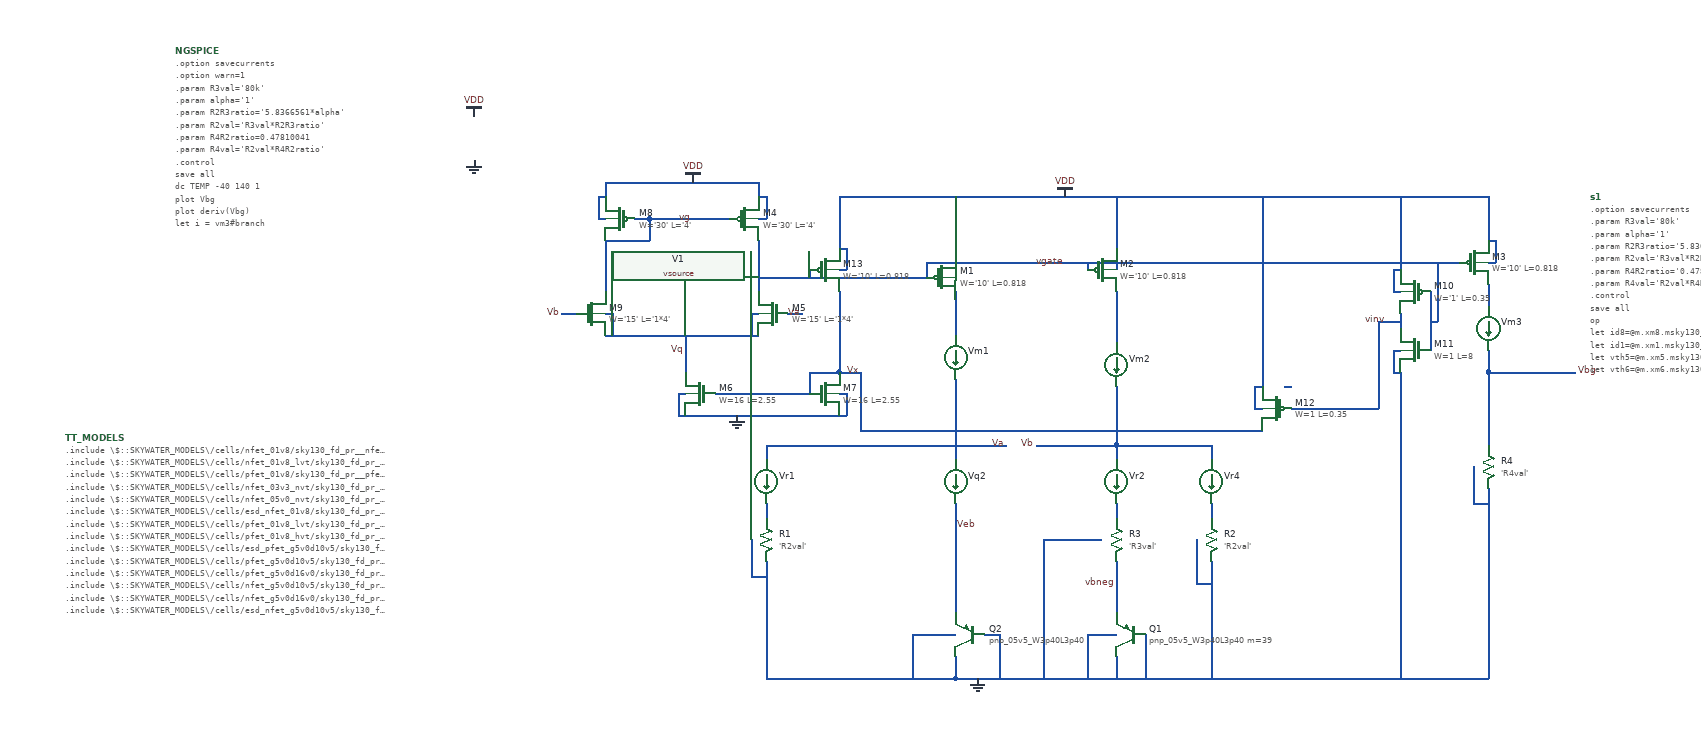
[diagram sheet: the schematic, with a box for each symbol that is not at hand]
v {xschem version=2.9.9 file_version=1.2 }
G {}
K {}
V {}
S {}
E {}
N 210 -180 460 -180 { lab=Va}
N 590 -180 690 -180 { lab=Vb}
N 690 -180 820 -180 { lab=Vb}
N 470 110 470 140 { lab=GND}
N 470 140 570 140 { lab=GND}
N 280 140 470 140 { lab=GND}
N 410 80 470 80 { lab=GND}
N 410 80 410 140 { lab=GND}
N 530 -180 540 -180 { lab=Va}
N 400 -520 620 -520 { lab=VDD}
N 620 -520 880 -520 { lab=VDD}
N 1200 -280 1320 -280 { lab=Vbg}
N 690 -180 690 -160 { lab=Vb}
N 690 -260 690 -180 { lab=Vb}
N 1200 -310 1200 -280 { lab=Vbg}
N 1200 -280 1200 -180 { lab=Vbg}
N 690 -100 690 -80 { lab=#net1}
N 820 -180 820 -160 { lab=Vb}
N 820 -100 820 -80 { lab=#net2}
N 210 -180 210 -160 { lab=Va}
N 210 -100 210 -80 { lab=#net3}
N 690 -390 690 -320 { lab=#net4}
N 690 -20 690 0 { lab=vbneg}
N 690 0 690 40 { lab=vbneg}
N 690 40 690 50 { lab=vbneg}
N 570 140 690 140 { lab=GND}
N 210 -20 210 140 { lab=GND}
N 820 -20 820 140 { lab=GND}
N 1200 -120 1200 140 { lab=GND}
N 620 140 880 140 { lab=GND}
N 730 80 730 140 { lab=GND}
N 470 -180 470 -160 { lab=Va}
N 690 110 690 140 { lab=GND}
N 650 80 690 80 { lab=GND}
N 650 80 650 140 { lab=GND}
N 510 80 530 80 { lab=GND}
N 530 80 530 140 { lab=GND}
N 190 -50 190 0 { lab=GND}
N 190 0 210 0 { lab=GND}
N 800 -50 800 10 { lab=GND}
N 800 10 820 10 { lab=GND}
N 590 -50 670 -50 { lab=GND}
N 590 -50 590 140 { lab=GND}
N 1180 -150 1180 -100 { lab=GND}
N 1180 -100 1200 -100 { lab=GND}
N 470 -100 470 50 { lab=Veb}
N 690 -460 690 -450 { lab=VDD}
N 1200 -380 1200 -370 { lab=#net5}
N 470 -270 470 -170 { lab=Va}
N 580 -180 590 -180 { lab=Vb}
N 470 -390 470 -330 { lab=#net6}
N 690 -450 690 -420 { lab=VDD}
N 430 -430 430 -420 { lab=vgate}
N 470 -450 470 -420 { lab=VDD}
N -10 -460 50 -460 { lab=vg}
N 50 -490 50 -460 { lab=vg}
N 30 -490 50 -490 { lab=vg}
N 50 -490 160 -490 { lab=vg}
N -10 -540 -10 -520 { lab=VDD}
N -10 -540 200 -540 { lab=VDD}
N 200 -540 200 -520 { lab=VDD}
N -10 -460 -10 -390 { lab=vg}
N 200 -460 200 -390 { lab=vgate}
N 240 -360 260 -360 { lab=Va}
N -70 -360 -50 -360 { lab=Vb}
N -10 -330 200 -330 { lab=Vq}
N 200 -490 210 -490 { lab=VDD}
N 210 -520 210 -490 { lab=VDD}
N 200 -520 210 -520 { lab=VDD}
N -20 -490 -10 -490 { lab=VDD}
N -20 -520 -20 -490 { lab=VDD}
N -20 -520 -10 -520 { lab=VDD}
N -10 -360 0 -360 { lab=Vq}
N 0 -360 0 -330 { lab=Vq}
N 190 -360 200 -360 { lab=Vq}
N 190 -360 190 -330 { lab=Vq}
N 90 -250 100 -250 { lab=GND}
N 90 -250 90 -220 { lab=GND}
N 90 -220 100 -220 { lab=GND}
N 100 -330 100 -280 { lab=Vq}
N 140 -250 270 -250 { lab=Vx}
N 310 -250 320 -250 { lab=GND}
N 310 -390 310 -280 { lab=Vx}
N 310 -520 360 -520 { lab=VDD}
N 170 -220 310 -220 { lab=GND}
N 100 -220 170 -220 { lab=GND}
N 270 -280 270 -250 { lab=Vx}
N 270 -280 310 -280 { lab=Vx}
N 310 -520 310 -450 { lab=VDD}
N 360 -520 400 -520 { lab=VDD}
N 430 -420 430 -410 { lab=vgate}
N 200 -410 360 -410 { lab=vgate}
N 320 -250 320 -220 { lab=GND}
N 310 -220 320 -220 { lab=GND}
N 270 -420 270 -410 { lab=vgate}
N 310 -420 320 -420 { lab=VDD}
N 320 -450 320 -420 { lab=VDD}
N 310 -450 320 -450 { lab=VDD}
N 1080 -520 1080 -420 { lab=VDD}
N 1120 -390 1120 -310 { lab=vgate}
N 1070 -390 1080 -390 { lab=VDD}
N 1070 -420 1070 -390 { lab=VDD}
N 1070 -420 1080 -420 { lab=VDD}
N 1080 -360 1080 -340 { lab=vinv}
N 1070 -310 1080 -310 { lab=GND}
N 1070 -310 1070 -280 { lab=GND}
N 1070 -280 1080 -280 { lab=GND}
N 1080 -280 1080 140 { lab=GND}
N 1120 -350 1130 -350 { lab=vgate}
N 1130 -430 1130 -350 { lab=vgate}
N 890 -520 890 -260 { lab=VDD}
N 880 -230 890 -230 { lab=VDD}
N 880 -260 880 -230 { lab=VDD}
N 920 -260 930 -260 { lab=#net7}
N 1050 -350 1050 -230 { lab=vinv}
N 1050 -350 1080 -350 { lab=vinv}
N 880 -520 1170 -520 { lab=VDD}
N 880 140 1170 140 { lab=GND}
N 340 -200 890 -200 { lab=Vx}
N 340 -280 340 -200 { lab=Vx}
N 310 -280 340 -280 { lab=Vx}
N 870 -430 1160 -430 { lab=vgate}
N 460 -180 530 -180 { lab=Va}
N 210 140 280 140 { lab=GND}
N 470 -520 470 -450 { lab=VDD}
N 690 -520 690 -460 { lab=VDD}
N 360 -410 430 -410 { lab=vgate}
N 430 -430 620 -430 { lab=vgate}
N 620 -430 870 -430 { lab=vgate}
N 650 -430 650 -420 { lab=vgate}
N 880 -260 890 -260 { lab=VDD}
N 1170 -520 1200 -520 { lab=VDD}
N 930 -230 1050 -230 { lab=vinv}
N 1170 140 1200 140 { lab=GND}
N 1200 -400 1200 -380 { lab=#net5}
N 1200 -430 1210 -430 { lab=VDD}
N 1210 -460 1210 -430 { lab=VDD}
N 1200 -460 1210 -460 { lab=VDD}
N 1200 -520 1200 -460 { lab=VDD}
N 470 -420 470 -410 { lab=VDD}
C {sky130_fd_pr/pnp_05v5.sym} 490 80 0 1 {name=Q2
model=pnp_05v5_W3p40L3p40
spiceprefix=X
}
C {devices/gnd.sym} 500 140 0 0 {name=l1 lab=GND}
C {devices/lab_pin.sym} 1320 -280 0 1 {name=l3 lab=Vbg}
C {devices/lab_pin.sym} 540 -180 3 0 {name=l5 lab=Va}
C {devices/lab_pin.sym} 580 -180 3 0 {name=l6 lab=Vb}
C {devices/code.sym} -750 -190 0 0 {name=TT_MODELS
only_toplevel=true
format="tcleval( @value )"
value="
.include \\\\$::SKYWATER_MODELS\\\\/cells/nfet_01v8/sky130_fd_pr__nfet_01v8__tt.corner.spice
.include \\\\$::SKYWATER_MODELS\\\\/cells/nfet_01v8_lvt/sky130_fd_pr__nfet_01v8_lvt__tt.corner.spice
.include \\\\$::SKYWATER_MODELS\\\\/cells/pfet_01v8/sky130_fd_pr__pfet_01v8__tt.corner.spice
.include \\\\$::SKYWATER_MODELS\\\\/cells/nfet_03v3_nvt/sky130_fd_pr__nfet_03v3_nvt__tt.corner.spice
.include \\\\$::SKYWATER_MODELS\\\\/cells/nfet_05v0_nvt/sky130_fd_pr__nfet_05v0_nvt__tt.corner.spice
.include \\\\$::SKYWATER_MODELS\\\\/cells/esd_nfet_01v8/sky130_fd_pr__esd_nfet_01v8__tt.corner.spice
.include \\\\$::SKYWATER_MODELS\\\\/cells/pfet_01v8_lvt/sky130_fd_pr__pfet_01v8_lvt__tt.corner.spice
.include \\\\$::SKYWATER_MODELS\\\\/cells/pfet_01v8_hvt/sky130_fd_pr__pfet_01v8_hvt__tt.corner.spice
.include \\\\$::SKYWATER_MODELS\\\\/cells/esd_pfet_g5v0d10v5/sky130_fd_pr__esd_pfet_g5v0d10v5__tt.corner.spice
.include \\\\$::SKYWATER_MODELS\\\\/cells/pfet_g5v0d10v5/sky130_fd_pr__pfet_g5v0d10v5__tt.corner.spice
.include \\\\$::SKYWATER_MODELS\\\\/cells/pfet_g5v0d16v0/sky130_fd_pr__pfet_g5v0d16v0__tt.corner.spice
.include \\\\$::SKYWATER_MODELS\\\\/cells/nfet_g5v0d10v5/sky130_fd_pr__nfet_g5v0d10v5__tt.corner.spice
.include \\\\$::SKYWATER_MODELS\\\\/cells/nfet_g5v0d16v0/sky130_fd_pr__nfet_g5v0d16v0__tt_discrete.corner.spice
.include \\\\$::SKYWATER_MODELS\\\\/cells/esd_nfet_g5v0d10v5/sky130_fd_pr__esd_nfet_g5v0d10v5__tt.corner.spice
.include \\\\$::SKYWATER_MODELS\\\\/models/corners/tt/nonfet.spice
* Mismatch parameters
.include \\\\$::SKYWATER_MODELS\\\\/cells/nfet_01v8/sky130_fd_pr__nfet_01v8__mismatch.corner.spice
.include \\\\$::SKYWATER_MODELS\\\\/cells/pfet_01v8/sky130_fd_pr__pfet_01v8__mismatch.corner.spice
.include \\\\$::SKYWATER_MODELS\\\\/cells/nfet_01v8_lvt/sky130_fd_pr__nfet_01v8_lvt__mismatch.corner.spice
.include \\\\$::SKYWATER_MODELS\\\\/cells/pfet_01v8_lvt/sky130_fd_pr__pfet_01v8_lvt__mismatch.corner.spice
.include \\\\$::SKYWATER_MODELS\\\\/cells/pfet_01v8_hvt/sky130_fd_pr__pfet_01v8_hvt__mismatch.corner.spice
.include \\\\$::SKYWATER_MODELS\\\\/cells/nfet_g5v0d10v5/sky130_fd_pr__nfet_g5v0d10v5__mismatch.corner.spice
.include \\\\$::SKYWATER_MODELS\\\\/cells/pfet_g5v0d10v5/sky130_fd_pr__pfet_g5v0d10v5__mismatch.corner.spice
.include \\\\$::SKYWATER_MODELS\\\\/cells/nfet_05v0_nvt/sky130_fd_pr__nfet_05v0_nvt__mismatch.corner.spice
.include \\\\$::SKYWATER_MODELS\\\\/cells/nfet_03v3_nvt/sky130_fd_pr__nfet_03v3_nvt__mismatch.corner.spice
* Resistor\\\\$::SKYWATER_MODELS\\\\/Capacitor
.include \\\\$::SKYWATER_MODELS\\\\/models/r+c/res_typical__cap_typical.spice
.include \\\\$::SKYWATER_MODELS\\\\/models/r+c/res_typical__cap_typical__lin.spice
* Special cells
.include \\\\$::SKYWATER_MODELS\\\\/models/corners/tt/specialized_cells.spice
* All models
.include \\\\$::SKYWATER_MODELS\\\\/models/all.spice
.include \\\\$::SKYWATER_MODELS\\\\/cells/pnp_05v5/sky130_fd_pr__pnp_05v5_W3p40L3p40.model.spice
* Corner
.include \\\\$::SKYWATER_MODELS\\\\/models/corners/tt/rf.spice
"}
C {devices/code_shown.sym} -600 -720 0 0 {name=NGSPICE
only_toplevel=true
spice_ignore=true
value="
.option savecurrents
.option warn=1
.param R3val='80k'
.param alpha='1'
.param R2R3ratio='5.8366561*alpha'
.param R2val='R3val*R2R3ratio' 
.param R4R2ratio=0.47810041
.param R4val='R2val*R4R2ratio'
.control
save all
dc TEMP -40 140 1
plot Vbg
plot deriv(Vbg)
let i = vm3#branch
let indx = 67
*indx is the index of temperature sweep for 27degC
echo 'Vbg @ 27degC'
let vbg27c = vbg[indx]
print vbg27c
echo 'dVbe/degC & ppm @ 27degC'
print deriv(vbg)[indx] deriv(vbg)[indx]/vbg27c
echo 'ppm real'
print (vbg[110]-vbg[40])/vbg[67]/(70-0)*1e6
plot deriv(vbg)/vbg27c
plot v(va, vb) vs i
plot vm1#branch vm2#branch vm3#branch
let vsg = vdd - vgate
let vsd1 = vdd - va
let vsd2 = vdd - vb
let vsd3 = vdd - vbg
let vthp = @m.xm1.msky130_fd_pr__pfet_01v8_lvt['vth']
let vov = vsg - vthp
plot vov vsd1 vsd2 vsd3
let deltav = vb - vbneg
let r4 =vbg/@r4[i]
let r1 =va/@r1[i]
let r2 =vb/@r2[i]
let r3 =deltav/@r3[i]
let vptat =(r2/r3*deltav)
let sum = veb+vptat
plot veb vptat sum
plot deriv(veb) deriv(vptat)
let TCratio=deriv(veb)/deriv(vptat)
plot TCratio
plot vb - va
echo 'alpha correction factor'
let alpha=TCratio[indx]
print alpha
let gm1=@m.xm1.msky130_fd_pr__pfet_01v8_lvt[gm]
let gm2=@m.xm2.msky130_fd_pr__pfet_01v8_lvt[gm]
let Av2=gm2 * ((r3 + r3/ln(39)) * r2 / (r3 + r3/ln(39) + r2) )
let Av1=gm1 * (r1 * r3/ln(39))/(r1 + r3/ln(39))
plot Av1 Av2 Av2/Av1
*write tsmc_bandgap_temp.raw
*op
*write tsmc_bandgap_op.raw
*print vbg 
*print (vb - vbneg)
.endc
" }
C {devices/vsource.sym} -190 -600 0 0 {name=V1 net_name=true value=1.8}
C {devices/vdd.sym} 620 -520 0 0 {name=l7 lab=VDD}
C {devices/vdd.sym} -190 -630 0 0 {name=l8 lab=VDD}
C {devices/gnd.sym} -190 -570 0 0 {name=l9 lab=GND}
C {devices/ammeter.sym} 820 -130 0 0 {name=Vr4}
C {devices/ammeter.sym} 690 -130 0 0 {name=Vr2}
C {devices/ammeter.sym} 470 -300 0 0 {name=Vm1}
C {devices/ammeter.sym} 690 -290 0 0 {name=Vm2}
C {devices/ammeter.sym} 1200 -340 0 0 {name=Vm3}
C {devices/ammeter.sym} 210 -130 0 0 {name=Vr1}
C {devices/ammeter.sym} 470 -130 0 0 {name=Vq2}
C {sky130_fd_pr/pnp_05v5.sym} 710 80 0 1 {name=Q1
model="pnp_05v5_W3p40L3p40 m=39"
spiceprefix=X
}
C {devices/lab_pin.sym} 690 10 0 0 {name=l4 lab=vbneg}
C {devices/lab_pin.sym} 470 -70 2 0 {name=l10 lab=Veb}
C {devices/lab_wire.sym} 620 -430 0 0 {name=l11 lab=vgate}
C {devices/res.sym} 690 -50 0 0 {name=R3
value='R3val'
footprint=1206
device=resistor
m=1
tc1=-1.47e-3
tc2=2.7e-6}
C {devices/res.sym} 1200 -150 0 0 {name=R4
value='R4val'
footprint=1206
device=resistor
m=1
tc1=-1.47e-3
tc2=2.7e-6}
C {devices/res.sym} 210 -50 0 0 {name=R1
value='R2val'
footprint=1206
device=resistor
m=1
tc1=-1.47e-3
tc2=2.7e-6}
C {devices/res.sym} 820 -50 0 0 {name=R2
value='R2val'
footprint=1206
device=resistor
m=1
tc1=-1.47e-3
tc2=2.7e-6}
C {devices/vdd.sym} 110 -540 0 0 {name=l14 lab=VDD}
C {devices/lab_pin.sym} -70 -360 3 0 {name=l15 lab=Vb}
C {devices/lab_pin.sym} 260 -360 3 0 {name=l16 lab=Va}
C {devices/gnd.sym} 170 -220 0 0 {name=l17 lab=GND}
C {sky130_fd_pr/pfet_01v8_lvt.sym} 180 -490 0 0 {name=M4
L='4'
W='30'
nf=1
mult=1
ad="'int((nf+1)/2) * W/nf * 0.29'" 
pd="'2*int((nf+1)/2) * (W/nf + 0.29)'"
as="'int((nf+2)/2) * W/nf * 0.29'" 
ps="'2*int((nf+2)/2) * (W/nf + 0.29)'"
nrd="'0.29 / W'" nrs="'0.29 / W'"
sa=0 sb=0 sd=0
model=pfet_01v8_lvt
spiceprefix=X
}
C {sky130_fd_pr/nfet_01v8_lvt.sym} 220 -360 0 1 {name=M5
L='1*4'
W='15'
nf=1
mult=16
ad="'int((nf+1)/2) * W/nf * 0.29'" 
pd="'2*int((nf+1)/2) * (W/nf + 0.29)'"
as="'int((nf+2)/2) * W/nf * 0.29'" 
ps="'2*int((nf+2)/2) * (W/nf + 0.29)'"
nrd="'0.29 / W'" nrs="'0.29 / W'"
sa=0 sb=0 sd=0
model=nfet_01v8_lvt
spiceprefix=X
}
C {sky130_fd_pr/nfet_01v8_lvt.sym} 120 -250 0 1 {name=M6
L=2.55
W=16
nf=1
mult=16
ad="'int((nf+1)/2) * W/nf * 0.29'" 
pd="'2*int((nf+1)/2) * (W/nf + 0.29)'"
as="'int((nf+2)/2) * W/nf * 0.29'" 
ps="'2*int((nf+2)/2) * (W/nf + 0.29)'"
nrd="'0.29 / W'" nrs="'0.29 / W'"
sa=0 sb=0 sd=0
model=nfet_01v8_lvt
spiceprefix=X
}
C {sky130_fd_pr/pfet_01v8_lvt.sym} 10 -490 0 1 {name=M8
L='4'
W='30'
nf=1
mult=1
ad="'int((nf+1)/2) * W/nf * 0.29'" 
pd="'2*int((nf+1)/2) * (W/nf + 0.29)'"
as="'int((nf+2)/2) * W/nf * 0.29'" 
ps="'2*int((nf+2)/2) * (W/nf + 0.29)'"
nrd="'0.29 / W'" nrs="'0.29 / W'"
sa=0 sb=0 sd=0
model=pfet_01v8_lvt
spiceprefix=X
}
C {sky130_fd_pr/nfet_01v8_lvt.sym} -30 -360 0 0 {name=M9
L='1*4'
W='15'
nf=1
mult=16
ad="'int((nf+1)/2) * W/nf * 0.29'" 
pd="'2*int((nf+1)/2) * (W/nf + 0.29)'"
as="'int((nf+2)/2) * W/nf * 0.29'" 
ps="'2*int((nf+2)/2) * (W/nf + 0.29)'"
nrd="'0.29 / W'" nrs="'0.29 / W'"
sa=0 sb=0 sd=0
model=nfet_01v8_lvt
spiceprefix=X
}
C {sky130_fd_pr/pfet_01v8_lvt.sym} 1100 -390 0 1 {name=M10
L=0.35
W='1'
nf=1
mult=50
ad="'int((nf+1)/2) * W/nf * 0.29'" 
pd="'2*int((nf+1)/2) * (W/nf + 0.29)'"
as="'int((nf+2)/2) * W/nf * 0.29'" 
ps="'2*int((nf+2)/2) * (W/nf + 0.29)'"
nrd="'0.29 / W'" nrs="'0.29 / W'"
sa=0 sb=0 sd=0
model=pfet_01v8_lvt
spiceprefix=X
}
C {sky130_fd_pr/nfet_01v8_lvt.sym} 1100 -310 0 1 {name=M11
L=8
W=1
nf=1
mult=1
ad="'int((nf+1)/2) * W/nf * 0.29'" 
pd="'2*int((nf+1)/2) * (W/nf + 0.29)'"
as="'int((nf+2)/2) * W/nf * 0.29'" 
ps="'2*int((nf+2)/2) * (W/nf + 0.29)'"
nrd="'0.29 / W'" nrs="'0.29 / W'"
sa=0 sb=0 sd=0
model=nfet_01v8_lvt
spiceprefix=X
}
C {sky130_fd_pr/pfet_01v8_lvt.sym} 910 -230 0 1 {name=M12
L=0.35
W=1
nf=1
mult=1
ad="'int((nf+1)/2) * W/nf * 0.29'" 
pd="'2*int((nf+1)/2) * (W/nf + 0.29)'"
as="'int((nf+2)/2) * W/nf * 0.29'" 
ps="'2*int((nf+2)/2) * (W/nf + 0.29)'"
nrd="'0.29 / W'" nrs="'0.29 / W'"
sa=0 sb=0 sd=0
model=pfet_01v8_lvt
spiceprefix=X
}
C {devices/lab_pin.sym} 110 -490 1 0 {name=l2 lab=vg}
C {devices/lab_pin.sym} 340 -280 1 0 {name=l12 lab=Vx}
C {devices/lab_pin.sym} 1060 -350 0 0 {name=l13 lab=vinv}
C {devices/lab_pin.sym} 100 -310 0 0 {name=l18 lab=Vq}
C {devices/code_shown.sym} 1340 -520 0 0 {name=s1 
only_toplevel=true 
spice_ignore=false
value="
.option savecurrents
.param R3val='80k'
.param alpha='1'
.param R2R3ratio='5.8366561*alpha'
.param R2val='R3val*R2R3ratio'
.param R4R2ratio='0.47810041'
.param R4val='R2val*R4R2ratio'
.control
save all
op
let id8=@m.xm8.msky130_fd_pr__pfet_01v8_lvt[id]
let id1=@m.xm1.msky130_fd_pr__pfet_01v8_lvt[id]
let vth5=@m.xm5.msky130_fd_pr__nfet_01v8_lvt[vth]
let vth6=@m.xm6.msky130_fd_pr__nfet_01v8_lvt[vth]
let wm8=@m.xm8.msky130_fd_pr__pfet_01v8_lvt[w]
let mm8=@m.xm8.msky130_fd_pr__pfet_01v8_lvt[m]
let weff8=wm8*mm8
let jd8=id8/weff8
let wm1=@m.xm1.msky130_fd_pr__pfet_01v8_lvt[w]
let mm1=@m.xm1.msky130_fd_pr__pfet_01v8_lvt[m]
let weff1=wm1*mm1
let jd1=id1/weff1
print vbg vgate vg va vb vx vinv vq
dc temp 27 0 -1
plot Vbg
dc temp 27 70 1
plot Vbg
.endc
"}
C {sky130_fd_pr/nfet_01v8_lvt.sym} 290 -250 0 0 {name=M7
L=2.55
W=16
nf=1
mult=16
ad="'int((nf+1)/2) * W/nf * 0.29'" 
pd="'2*int((nf+1)/2) * (W/nf + 0.29)'"
as="'int((nf+2)/2) * W/nf * 0.29'" 
ps="'2*int((nf+2)/2) * (W/nf + 0.29)'"
nrd="'0.29 / W'" nrs="'0.29 / W'"
sa=0 sb=0 sd=0
model=nfet_01v8_lvt
spiceprefix=X
}
C {sky130_fd_pr/pfet_01v8_lvt.sym} 290 -420 0 0 {name=M13
L=0.818
W='10'
nf=1
mult=1
ad="'int((nf+1)/2) * W/nf * 0.29'" 
pd="'2*int((nf+1)/2) * (W/nf + 0.29)'"
as="'int((nf+2)/2) * W/nf * 0.29'" 
ps="'2*int((nf+2)/2) * (W/nf + 0.29)'"
nrd="'0.29 / W'" nrs="'0.29 / W'"
sa=0 sb=0 sd=0
model=pfet_01v8_lvt
spiceprefix=X
}
C {sky130_fd_pr/pfet_01v8_lvt.sym} 450 -410 0 0 {name=M1
L=0.818
W='10'
nf=1
mult=1
ad="'int((nf+1)/2) * W/nf * 0.29'" 
pd="'2*int((nf+1)/2) * (W/nf + 0.29)'"
as="'int((nf+2)/2) * W/nf * 0.29'" 
ps="'2*int((nf+2)/2) * (W/nf + 0.29)'"
nrd="'0.29 / W'" nrs="'0.29 / W'"
sa=0 sb=0 sd=0
model=pfet_01v8_lvt
spiceprefix=X
}
C {sky130_fd_pr/pfet_01v8_lvt.sym} 670 -420 0 0 {name=M2
L=0.818
W='10'
nf=1
mult=1
ad="'int((nf+1)/2) * W/nf * 0.29'" 
pd="'2*int((nf+1)/2) * (W/nf + 0.29)'"
as="'int((nf+2)/2) * W/nf * 0.29'" 
ps="'2*int((nf+2)/2) * (W/nf + 0.29)'"
nrd="'0.29 / W'" nrs="'0.29 / W'"
sa=0 sb=0 sd=0
model=pfet_01v8_lvt
spiceprefix=X
}
C {sky130_fd_pr/pfet_01v8_lvt.sym} 1180 -430 0 0 {name=M3
L=0.818
W='10'
nf=1
mult=1
ad="'int((nf+1)/2) * W/nf * 0.29'" 
pd="'2*int((nf+1)/2) * (W/nf + 0.29)'"
as="'int((nf+2)/2) * W/nf * 0.29'" 
ps="'2*int((nf+2)/2) * (W/nf + 0.29)'"
nrd="'0.29 / W'" nrs="'0.29 / W'"
sa=0 sb=0 sd=0
model=pfet_01v8_lvt
spiceprefix=X
}
